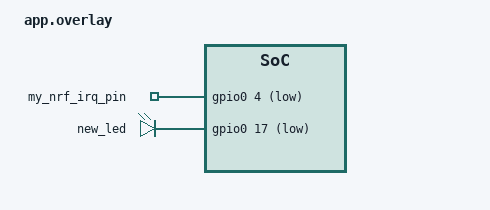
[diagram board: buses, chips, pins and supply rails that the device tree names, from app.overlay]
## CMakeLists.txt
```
# SPDX-License-Identifier: Apache-2.0
cmake_minimum_required(VERSION 3.20.0)
# openocd runner configuration
set(BOARD_FLASH_RUNNER openocd)
set(BOARD_DEBUG_RUNNER openocd)


find_package(Zephyr REQUIRED HINTS $ENV{ZEPHYR_BASE})
project(NRF_BLE)

include(${ZEPHYR_BASE}/boards/common/openocd.board.cmake)

# using include for openocd
board_runner_args(openocd
    "--cmd-pre-init=source [find interface/stlink.cfg]"
    "--cmd-pre-init=transport select swd"
    "--cmd-pre-init=source [find target/nordic/nrf52.cfg]")
message(STATUS ">>> runner args applied")   

target_sources(app PRIVATE src/main.c src/test.c src/new_led.c)
```

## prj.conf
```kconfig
CONFIG_GPIO=y
# For Portability using USB CDC ACM, though for XIAO is it not needed, but there is error in it.
# CONFIG_USB_DEVICE_STACK=y
# CONFIG_USB_DEVICE_INITIALIZE_AT_BOOT=y
# CONFIG_CONSOLE=y
CONFIG_UART_CONSOLE=y
CONFIG_UART_LINE_CTRL=y
```

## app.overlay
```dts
/ {
    aliases {
        nrf-irq = &my_nrf_irq_pin;
        new-led = &new_led;
    };

    custom_inputs {
        compatible = "gpio-keys";

        my_nrf_irq_pin: irq_pin {
            gpios = <&gpio0 4 (GPIO_ACTIVE_LOW | GPIO_PULL_UP)>;
        };
    };

    custom_outputs {
        compatible = "gpio-leds";
        new_led: led {
            gpios = <&gpio0 17 GPIO_ACTIVE_LOW>;

        };
    };
};
```

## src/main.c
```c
#include <zephyr/kernel.h>
#include <zephyr/drivers/gpio.h>
#include <zephyr/sys/printk.h>
#include "test.h"
#include "new_led.h"

int main(void)
{
        while(1){
          new_led();
          k_msleep(1000);
          printk("main code running\n");
        }
        return 0;
}
```

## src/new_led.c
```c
#include <zephyr/kernel.h>
#include <zephyr/drivers/gpio.h>
#include <zephyr/sys/printk.h>
#define set_delay 500
int new_led(){
    const struct gpio_dt_spec my_pin = GPIO_DT_SPEC_GET(DT_ALIAS(new_led), gpios);
    gpio_pin_configure_dt(&my_pin, GPIO_OUTPUT_INACTIVE);
    gpio_pin_set_dt(&my_pin, 1);
    k_msleep(set_delay);
    gpio_pin_set_dt(&my_pin, 0);
    k_msleep(set_delay);
    return 0;
}
void new_led_thread(void *p1, void *p2, void *p3)
{
        while (1)
        {
            new_led();
        }
}
K_THREAD_DEFINE(new_led_thread_id, 1024, new_led_thread, NULL, NULL, NULL, 7, 0, 0);
```

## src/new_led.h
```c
#ifndef new_led_h
#define new_led_h
int new_led(void);
#endif
```

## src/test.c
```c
#include <zephyr/kernel.h>
#include <zephyr/drivers/gpio.h>
#include <zephyr/sys/printk.h>

#define set_delay 500

#define led1_xiao DT_ALIAS(led0)
#define led2_xiao DT_ALIAS(led1)
#define led3_xiao DT_ALIAS(led2)
#define irq_handler DT_ALIAS(nrf_irq) // where it is??

static const struct gpio_dt_spec blue_led = GPIO_DT_SPEC_GET(led1_xiao, gpios);
static const struct gpio_dt_spec red_led = GPIO_DT_SPEC_GET(led2_xiao, gpios);
static const struct gpio_dt_spec green_led = GPIO_DT_SPEC_GET(led3_xiao, gpios);

static const struct gpio_dt_spec irq_pin = GPIO_DT_SPEC_GET(irq_handler, gpios);
static struct gpio_callback irq_cb_data;

K_SEM_DEFINE(led_sem, 0, 1);

static void nrf_isr_handler(const struct device *dev, struct gpio_callback *cb, uint32_t pins)
{
        k_sem_give(&led_sem);
}

int init_led(void)
{
        gpio_pin_configure_dt(&red_led, GPIO_OUTPUT_INACTIVE);
        gpio_pin_configure_dt(&green_led, GPIO_OUTPUT_INACTIVE);
        gpio_pin_configure_dt(&blue_led, GPIO_OUTPUT_INACTIVE);
        return 0;
}
int led_toggle(const struct gpio_dt_spec *led, const char *name)
{
        gpio_pin_set_dt(led, 1);
        printk("%s is on\n", name);
        k_msleep(set_delay);
        gpio_pin_set_dt(led, 0);
        printk("%s is off\n", name);
        k_msleep(set_delay);
        return 0;
}
int test_run(void)
{

        led_toggle(&red_led, "red led");
        led_toggle(&green_led, "green led");
        led_toggle(&blue_led, "blue led");
        return 0;
}
void test_thread(void *p1, void *p2, void *p3)
{
        gpio_pin_configure_dt(&irq_pin, GPIO_INPUT);
        gpio_pin_interrupt_configure_dt(&irq_pin, GPIO_INT_EDGE_FALLING);
        gpio_init_callback(&irq_cb_data, nrf_isr_handler, BIT(irq_pin.pin));
        gpio_add_callback(irq_pin.port, &irq_cb_data);
        init_led();
        while (1)
        {
                k_sem_take(&led_sem, K_FOREVER);
                test_run();
        }
}
K_THREAD_DEFINE(test_thread_id, 1024, test_thread, NULL, NULL, NULL, 7, 0, 0);
```

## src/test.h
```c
#ifndef test_h
#define test_h
int init_led(void);
int test_run(void);
#endif
```
